One B-rep face of a CAD part: STEP entity #306.
In plain terms, the planar face has unit normal (1, 0, 0).
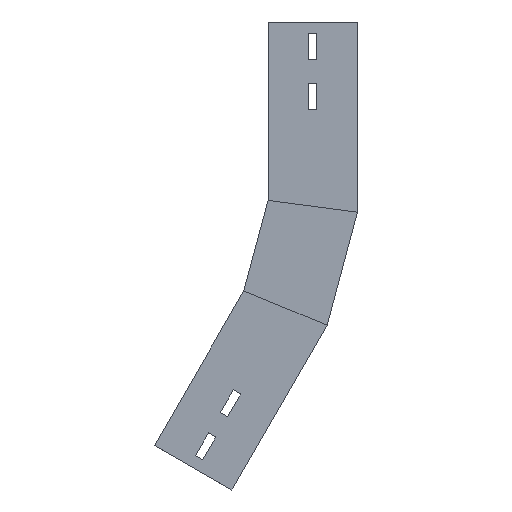
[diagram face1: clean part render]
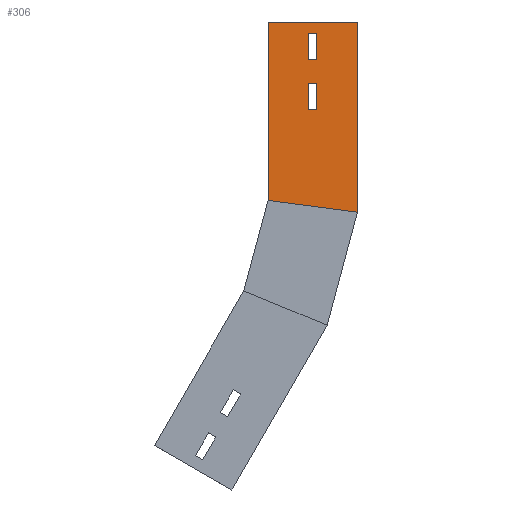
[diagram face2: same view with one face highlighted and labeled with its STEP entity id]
Its self-contained STEP definition (entity closure, numbers rounded to 3 decimals):
#4 = VERTEX_POINT ( 'NONE', #501 ) ;
#8 = VECTOR ( 'NONE', #1112, 1000. ) ;
#21 = EDGE_CURVE ( 'NONE', #726, #1408, #1407, .T. ) ;
#26 = FACE_OUTER_BOUND ( 'NONE', #647, .T. ) ;
#50 = CARTESIAN_POINT ( 'NONE',  ( 0., 170.244, -355.455 ) ) ;
#52 = DIRECTION ( 'NONE',  ( 0., 0.5, -0.866 ) ) ;
#57 = CARTESIAN_POINT ( 'NONE',  ( 0., 105.292, -392.955 ) ) ;
#79 = DIRECTION ( 'NONE',  ( 0., 0.5, -0.866 ) ) ;
#83 = ORIENTED_EDGE ( 'NONE', *, *, #129, .T. ) ;
#90 = CARTESIAN_POINT ( 'NONE',  ( 0., 135.881, -363.937 ) ) ;
#129 = EDGE_CURVE ( 'NONE', #4, #1447, #1011, .T. ) ;
#156 = VERTEX_POINT ( 'NONE', #407 ) ;
#165 = DIRECTION ( 'NONE',  ( 0., 0.866, 0.5 ) ) ;
#184 = DIRECTION ( 'NONE',  ( 0., 0.866, 0.5 ) ) ;
#195 = CARTESIAN_POINT ( 'NONE',  ( 0., 97.984, -312.298 ) ) ;
#203 = CARTESIAN_POINT ( 'NONE',  ( 0., 25.442, -254.651 ) ) ;
#205 = VECTOR ( 'NONE', #1249, 1000. ) ;
#220 = LINE ( 'NONE', #460, #205 ) ;
#222 = VECTOR ( 'NONE', #1448, 1000. ) ;
#263 = FACE_BOUND ( 'NONE', #721, .T. ) ;
#273 = VERTEX_POINT ( 'NONE', #90 ) ;
#277 = CARTESIAN_POINT ( 'NONE',  ( 0., 118.819, -348.385 ) ) ;
#278 = CARTESIAN_POINT ( 'NONE',  ( 0., 124.881, -344.885 ) ) ;
#285 = LINE ( 'NONE', #1110, #1415 ) ;
#306 = ADVANCED_FACE ( 'NONE', ( #1405, #263, #26 ), #1293, .F. ) ;
#314 = VECTOR ( 'NONE', #52, 1000. ) ;
#317 = AXIS2_PLACEMENT_3D ( 'NONE', #499, #963, #844 ) ;
#356 = CARTESIAN_POINT ( 'NONE',  ( 0., 124.881, -344.885 ) ) ;
#396 = VECTOR ( 'NONE', #707, 1000. ) ;
#401 = LINE ( 'NONE', #864, #314 ) ;
#403 = EDGE_CURVE ( 'NONE', #880, #1365, #1398, .T. ) ;
#407 = CARTESIAN_POINT ( 'NONE',  ( 0., 108.984, -331.35 ) ) ;
#417 = ORIENTED_EDGE ( 'NONE', *, *, #1368, .F. ) ;
#423 = LINE ( 'NONE', #1353, #967 ) ;
#460 = CARTESIAN_POINT ( 'NONE',  ( 0., 90.394, -217.151 ) ) ;
#462 = ORIENTED_EDGE ( 'NONE', *, *, #729, .F. ) ;
#474 = VERTEX_POINT ( 'NONE', #1431 ) ;
#481 = ORIENTED_EDGE ( 'NONE', *, *, #541, .T. ) ;
#499 = CARTESIAN_POINT ( 'NONE',  ( 0., 25.442, -254.651 ) ) ;
#501 = CARTESIAN_POINT ( 'NONE',  ( 0., 95.331, -225.702 ) ) ;
#529 = ORIENTED_EDGE ( 'NONE', *, *, #1193, .F. ) ;
#541 = EDGE_CURVE ( 'NONE', #1447, #474, #285, .T. ) ;
#545 = CARTESIAN_POINT ( 'NONE',  ( 0., 129.819, -367.437 ) ) ;
#550 = VERTEX_POINT ( 'NONE', #50 ) ;
#553 = EDGE_CURVE ( 'NONE', #474, #550, #1459, .T. ) ;
#564 = VECTOR ( 'NONE', #1306, 1000. ) ;
#571 = DIRECTION ( 'NONE',  ( 0., -0.5, 0.866 ) ) ;
#619 = ORIENTED_EDGE ( 'NONE', *, *, #403, .F. ) ;
#627 = DIRECTION ( 'NONE',  ( 0., 0.866, 0.5 ) ) ;
#645 = CARTESIAN_POINT ( 'NONE',  ( 0., 104.046, -308.798 ) ) ;
#647 = EDGE_LOOP ( 'NONE', ( #83, #481, #1172, #839 ) ) ;
#702 = DIRECTION ( 'NONE',  ( 0., -0.866, -0.5 ) ) ;
#707 = DIRECTION ( 'NONE',  ( 0., 0.5, -0.866 ) ) ;
#721 = EDGE_LOOP ( 'NONE', ( #462, #417, #529, #991 ) ) ;
#726 = VERTEX_POINT ( 'NONE', #1048 ) ;
#729 = EDGE_CURVE ( 'NONE', #1147, #726, #1386, .T. ) ;
#742 = LINE ( 'NONE', #1217, #1364 ) ;
#828 = ORIENTED_EDGE ( 'NONE', *, *, #1362, .F. ) ;
#839 = ORIENTED_EDGE ( 'NONE', *, *, #1083, .F. ) ;
#840 = CARTESIAN_POINT ( 'NONE',  ( 0., 115.046, -327.85 ) ) ;
#844 = DIRECTION ( 'NONE',  ( 0., 0., 1. ) ) ;
#847 = ORIENTED_EDGE ( 'NONE', *, *, #1382, .F. ) ;
#859 = EDGE_CURVE ( 'NONE', #1434, #273, #980, .T. ) ;
#864 = CARTESIAN_POINT ( 'NONE',  ( 0., 129.819, -367.437 ) ) ;
#865 = CARTESIAN_POINT ( 'NONE',  ( 0., 135.881, -363.937 ) ) ;
#880 = VERTEX_POINT ( 'NONE', #278 ) ;
#955 = ORIENTED_EDGE ( 'NONE', *, *, #859, .F. ) ;
#963 = DIRECTION ( 'NONE',  ( -1., 0., 0. ) ) ;
#967 = VECTOR ( 'NONE', #571, 1000. ) ;
#980 = LINE ( 'NONE', #865, #1142 ) ;
#991 = ORIENTED_EDGE ( 'NONE', *, *, #21, .F. ) ;
#1011 = LINE ( 'NONE', #1462, #8 ) ;
#1048 = CARTESIAN_POINT ( 'NONE',  ( 0., 104.046, -308.798 ) ) ;
#1070 = LINE ( 'NONE', #1300, #396 ) ;
#1083 = EDGE_CURVE ( 'NONE', #4, #550, #220, .T. ) ;
#1110 = CARTESIAN_POINT ( 'NONE',  ( 0., 25.442, -254.651 ) ) ;
#1112 = DIRECTION ( 'NONE',  ( 0., -0.924, -0.383 ) ) ;
#1142 = VECTOR ( 'NONE', #627, 1000. ) ;
#1147 = VERTEX_POINT ( 'NONE', #840 ) ;
#1172 = ORIENTED_EDGE ( 'NONE', *, *, #553, .T. ) ;
#1175 = EDGE_LOOP ( 'NONE', ( #847, #955, #828, #619 ) ) ;
#1193 = EDGE_CURVE ( 'NONE', #1408, #156, #1070, .T. ) ;
#1204 = VECTOR ( 'NONE', #702, 1000. ) ;
#1217 = CARTESIAN_POINT ( 'NONE',  ( 0., 115.046, -327.85 ) ) ;
#1249 = DIRECTION ( 'NONE',  ( 0., 0.5, -0.866 ) ) ;
#1293 = PLANE ( 'NONE',  #317 ) ;
#1300 = CARTESIAN_POINT ( 'NONE',  ( 0., 108.984, -331.35 ) ) ;
#1306 = DIRECTION ( 'NONE',  ( 0., -0.5, 0.866 ) ) ;
#1344 = VECTOR ( 'NONE', #184, 1000. ) ;
#1353 = CARTESIAN_POINT ( 'NONE',  ( 0., 135.881, -363.937 ) ) ;
#1362 = EDGE_CURVE ( 'NONE', #1365, #1434, #401, .T. ) ;
#1364 = VECTOR ( 'NONE', #165, 1000. ) ;
#1365 = VERTEX_POINT ( 'NONE', #277 ) ;
#1368 = EDGE_CURVE ( 'NONE', #156, #1147, #742, .T. ) ;
#1382 = EDGE_CURVE ( 'NONE', #273, #880, #423, .T. ) ;
#1386 = LINE ( 'NONE', #1422, #564 ) ;
#1398 = LINE ( 'NONE', #356, #1204 ) ;
#1405 = FACE_BOUND ( 'NONE', #1175, .T. ) ;
#1407 = LINE ( 'NONE', #645, #222 ) ;
#1408 = VERTEX_POINT ( 'NONE', #195 ) ;
#1415 = VECTOR ( 'NONE', #79, 1000. ) ;
#1422 = CARTESIAN_POINT ( 'NONE',  ( 0., 115.046, -327.85 ) ) ;
#1431 = CARTESIAN_POINT ( 'NONE',  ( 0., 105.292, -392.955 ) ) ;
#1434 = VERTEX_POINT ( 'NONE', #545 ) ;
#1447 = VERTEX_POINT ( 'NONE', #203 ) ;
#1448 = DIRECTION ( 'NONE',  ( 0., -0.866, -0.5 ) ) ;
#1459 = LINE ( 'NONE', #57, #1344 ) ;
#1462 = CARTESIAN_POINT ( 'NONE',  ( 0., 37.296, -249.74 ) ) ;
